VERSION 5.7 ;
  NOWIREEXTENSIONATPIN ON ;
  DIVIDERCHAR "/" ;
  BUSBITCHARS "[]" ;
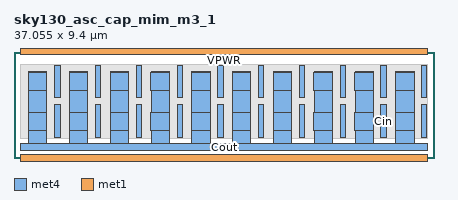
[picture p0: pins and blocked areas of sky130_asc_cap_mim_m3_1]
MACRO sky130_asc_cap_mim_m3_1
  CLASS CORE ;
  FOREIGN sky130_asc_cap_mim_m3_1 ;
  ORIGIN 0.000 0.000 ;
  SIZE 37.055 BY 9.400 ;
  SITE unitasc ;
  PIN Cin
    DIRECTION INOUT ;
    PORT
      LAYER met4 ;
        RECT 3.600 5.310 4.080 8.190 ;
        RECT 7.195 5.310 7.675 8.190 ;
        RECT 10.790 5.310 11.270 8.190 ;
        RECT 14.385 5.310 14.865 8.190 ;
        RECT 17.980 5.310 18.460 8.190 ;
        RECT 21.575 5.310 22.055 8.190 ;
        RECT 25.170 5.310 25.650 8.190 ;
        RECT 28.765 5.310 29.245 8.190 ;
        RECT 32.360 5.310 32.840 8.190 ;
        RECT 35.955 5.310 36.435 8.190 ;
        RECT 3.600 1.810 4.080 4.690 ;
        RECT 7.195 1.810 7.675 4.690 ;
        RECT 10.790 1.810 11.270 4.690 ;
        RECT 14.385 1.810 14.865 4.690 ;
        RECT 17.980 1.810 18.460 4.690 ;
        RECT 21.575 1.810 22.055 4.690 ;
        RECT 25.170 1.810 25.650 4.690 ;
        RECT 28.765 1.810 29.245 4.690 ;
        RECT 32.360 1.810 32.840 4.690 ;
        RECT 35.955 1.810 36.435 4.690 ;
    END
  END Cin
  PIN Cout
    DIRECTION INOUT ;
    PORT
      LAYER met4 ;
        RECT 1.300 7.555 2.900 7.650 ;
        RECT 4.900 7.555 6.500 7.650 ;
        RECT 8.500 7.555 10.100 7.650 ;
        RECT 12.100 7.555 13.700 7.650 ;
        RECT 15.700 7.555 17.300 7.650 ;
        RECT 19.300 7.555 20.900 7.650 ;
        RECT 22.900 7.555 24.500 7.650 ;
        RECT 26.500 7.555 28.100 7.650 ;
        RECT 30.100 7.555 31.700 7.650 ;
        RECT 33.700 7.555 35.300 7.650 ;
        RECT 1.300 5.945 2.910 7.555 ;
        RECT 4.895 5.945 6.505 7.555 ;
        RECT 8.490 5.945 10.100 7.555 ;
        RECT 12.085 5.945 13.700 7.555 ;
        RECT 15.680 5.945 17.300 7.555 ;
        RECT 19.275 5.945 20.900 7.555 ;
        RECT 22.870 5.945 24.500 7.555 ;
        RECT 26.465 5.945 28.100 7.555 ;
        RECT 30.060 5.945 31.700 7.555 ;
        RECT 33.655 5.945 35.300 7.555 ;
        RECT 1.300 4.055 2.900 5.945 ;
        RECT 4.900 4.055 6.500 5.945 ;
        RECT 8.500 4.055 10.100 5.945 ;
        RECT 12.100 4.055 13.700 5.945 ;
        RECT 15.700 4.055 17.300 5.945 ;
        RECT 19.300 4.055 20.900 5.945 ;
        RECT 22.900 4.055 24.500 5.945 ;
        RECT 26.500 4.055 28.100 5.945 ;
        RECT 30.100 4.055 31.700 5.945 ;
        RECT 33.700 4.055 35.300 5.945 ;
        RECT 1.300 2.445 2.910 4.055 ;
        RECT 4.895 2.445 6.505 4.055 ;
        RECT 8.490 2.445 10.100 4.055 ;
        RECT 12.085 2.445 13.700 4.055 ;
        RECT 15.680 2.445 17.300 4.055 ;
        RECT 19.275 2.445 20.900 4.055 ;
        RECT 22.870 2.445 24.500 4.055 ;
        RECT 26.465 2.445 28.100 4.055 ;
        RECT 30.060 2.445 31.700 4.055 ;
        RECT 33.655 2.445 35.300 4.055 ;
        RECT 1.300 1.250 2.900 2.445 ;
        RECT 4.900 1.250 6.500 2.445 ;
        RECT 8.500 1.250 10.100 2.445 ;
        RECT 12.100 1.250 13.700 2.445 ;
        RECT 15.700 1.250 17.300 2.445 ;
        RECT 19.300 1.250 20.900 2.445 ;
        RECT 22.900 1.250 24.500 2.445 ;
        RECT 26.500 1.250 28.100 2.445 ;
        RECT 30.100 1.250 31.700 2.445 ;
        RECT 33.700 1.250 35.300 2.445 ;
        RECT 0.610 0.650 36.450 1.250 ;
    END
  END Cout
  PIN VPWR
    DIRECTION INOUT ;
    USE POWER ;
    PORT
      LAYER met1 ;
        RECT 0.610 9.100 36.450 9.700 ;
    END
  END VPWR
  PIN VGND
    DIRECTION INOUT ;
    USE GROUND ;
    PORT
      LAYER met1 ;
        RECT 0.610 -0.300 36.450 0.300 ;
    END
  END VGND
  OBS
      LAYER li1 ;
        RECT 0.610 9.250 36.450 9.550 ;
        RECT 0.610 -0.150 36.450 0.150 ;
      LAYER mcon ;
        RECT 1.460 9.250 1.760 9.550 ;
        RECT 3.460 9.250 3.760 9.550 ;
        RECT 5.460 9.250 5.760 9.550 ;
        RECT 7.460 9.250 7.760 9.550 ;
        RECT 9.460 9.250 9.760 9.550 ;
        RECT 11.460 9.250 11.760 9.550 ;
        RECT 13.460 9.250 13.760 9.550 ;
        RECT 15.460 9.250 15.760 9.550 ;
        RECT 17.460 9.250 17.760 9.550 ;
        RECT 19.460 9.250 19.760 9.550 ;
        RECT 21.460 9.250 21.760 9.550 ;
        RECT 23.460 9.250 23.760 9.550 ;
        RECT 25.460 9.250 25.760 9.550 ;
        RECT 27.460 9.250 27.760 9.550 ;
        RECT 29.460 9.250 29.760 9.550 ;
        RECT 31.460 9.250 31.760 9.550 ;
        RECT 33.460 9.250 33.760 9.550 ;
        RECT 35.460 9.250 35.760 9.550 ;
        RECT 1.460 -0.150 1.760 0.150 ;
        RECT 3.460 -0.150 3.760 0.150 ;
        RECT 5.460 -0.150 5.760 0.150 ;
        RECT 7.460 -0.150 7.760 0.150 ;
        RECT 9.460 -0.150 9.760 0.150 ;
        RECT 11.460 -0.150 11.760 0.150 ;
        RECT 13.460 -0.150 13.760 0.150 ;
        RECT 15.460 -0.150 15.760 0.150 ;
        RECT 17.460 -0.150 17.760 0.150 ;
        RECT 19.460 -0.150 19.760 0.150 ;
        RECT 21.460 -0.150 21.760 0.150 ;
        RECT 23.460 -0.150 23.760 0.150 ;
        RECT 25.460 -0.150 25.760 0.150 ;
        RECT 27.460 -0.150 27.760 0.150 ;
        RECT 29.460 -0.150 29.760 0.150 ;
        RECT 31.460 -0.150 31.760 0.150 ;
        RECT 33.460 -0.150 33.760 0.150 ;
        RECT 35.460 -0.150 35.760 0.150 ;
      LAYER met2 ;
        RECT 0.600 7.850 1.600 8.250 ;
        RECT 0.710 0.700 1.510 1.200 ;
      LAYER via2 ;
        RECT 0.700 7.900 1.500 8.200 ;
        RECT 0.810 0.750 1.410 1.150 ;
      LAYER met3 ;
        RECT 0.600 1.750 36.460 8.250 ;
        RECT 0.610 0.650 1.610 1.250 ;
      LAYER via3 ;
        RECT 3.680 5.390 4.000 8.110 ;
        RECT 7.275 5.390 7.595 8.110 ;
        RECT 10.870 5.390 11.190 8.110 ;
        RECT 14.465 5.390 14.785 8.110 ;
        RECT 18.060 5.390 18.380 8.110 ;
        RECT 21.655 5.390 21.975 8.110 ;
        RECT 25.250 5.390 25.570 8.110 ;
        RECT 28.845 5.390 29.165 8.110 ;
        RECT 32.440 5.390 32.760 8.110 ;
        RECT 36.035 5.390 36.355 8.110 ;
        RECT 3.680 1.890 4.000 4.610 ;
        RECT 7.275 1.890 7.595 4.610 ;
        RECT 10.870 1.890 11.190 4.610 ;
        RECT 14.465 1.890 14.785 4.610 ;
        RECT 18.060 1.890 18.380 4.610 ;
        RECT 21.655 1.890 21.975 4.610 ;
        RECT 25.250 1.890 25.570 4.610 ;
        RECT 28.845 1.890 29.165 4.610 ;
        RECT 32.440 1.890 32.760 4.610 ;
        RECT 36.035 1.890 36.355 4.610 ;
        RECT 0.710 0.700 1.510 1.200 ;
  END
END sky130_asc_cap_mim_m3_1
END LIBRARY

